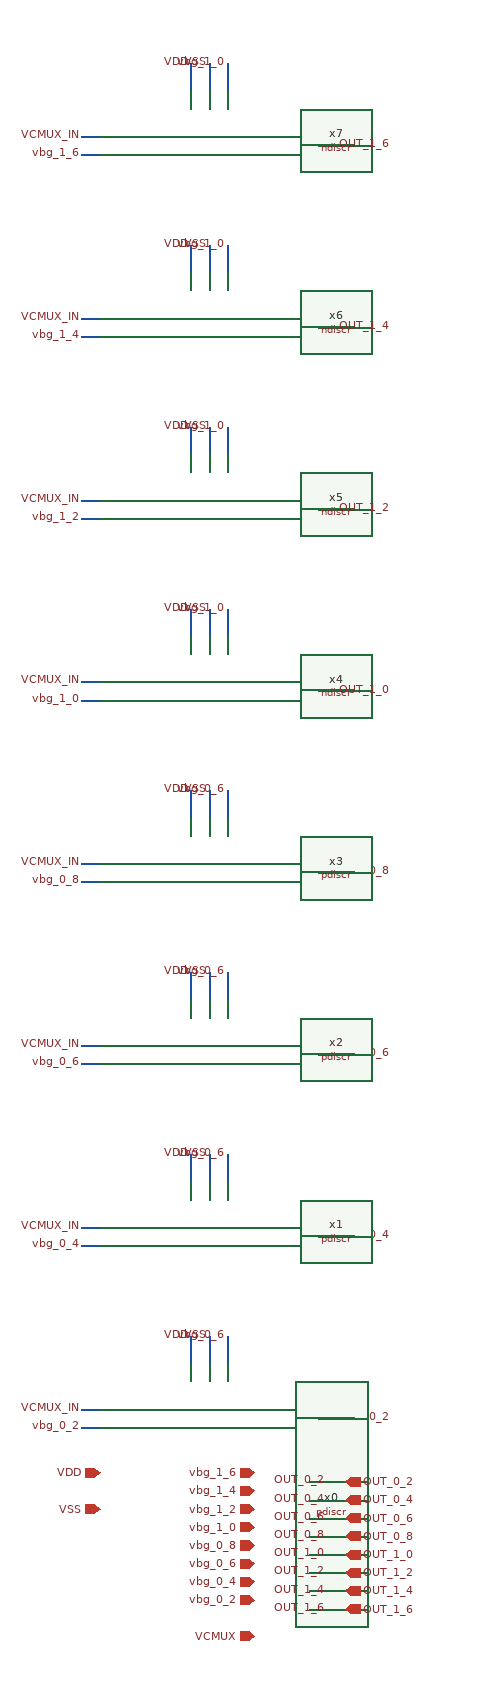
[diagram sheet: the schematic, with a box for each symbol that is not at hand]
v {xschem version=3.4.5 file_version=1.2
}
G {}
K {}
V {}
S {}
E {}
N 160 -130 160 -100 {
lab=vbg_0_6}
N 120 -130 120 -100 {
lab=VDD}
N 140 -130 140 -100 {
lab=VSS}
N 0 -50 20 -50 {
lab=VCMUX_IN}
N 0 -30 20 -30 {
lab=vbg_0_2}
N 260 -40 300 -40 {
lab=OUT_0_2}
N 160 -330 160 -300 {
lab=vbg_0_6}
N 120 -330 120 -300 {
lab=VDD}
N 140 -330 140 -300 {
lab=VSS}
N 0 -250 20 -250 {
lab=VCMUX_IN}
N 0 -230 20 -230 {
lab=vbg_0_4}
N 260 -240 300 -240 {
lab=OUT_0_4}
N 160 -530 160 -500 {
lab=vbg_0_6}
N 120 -530 120 -500 {
lab=VDD}
N 140 -530 140 -500 {
lab=VSS}
N 0 -450 20 -450 {
lab=VCMUX_IN}
N 0 -430 20 -430 {
lab=vbg_0_6}
N 260 -440 300 -440 {
lab=OUT_0_6}
N 160 -730 160 -700 {
lab=vbg_0_6}
N 120 -730 120 -700 {
lab=VDD}
N 140 -730 140 -700 {
lab=VSS}
N 0 -650 20 -650 {
lab=VCMUX_IN}
N 0 -630 20 -630 {
lab=vbg_0_8}
N 260 -640 300 -640 {
lab=OUT_0_8}
N 0 -850 20 -850 {
lab=VCMUX_IN}
N 0 -830 20 -830 {
lab=vbg_1_0}
N 160 -930 160 -900 {
lab=vbg_1_0}
N 120 -930 120 -900 {
lab=VDD}
N 140 -930 140 -900 {
lab=VSS}
N 260 -840 300 -840 {
lab=OUT_1_0}
N 0 -1050 20 -1050 {
lab=VCMUX_IN}
N 0 -1030 20 -1030 {
lab=vbg_1_2}
N 160 -1130 160 -1100 {
lab=vbg_1_0}
N 120 -1130 120 -1100 {
lab=VDD}
N 140 -1130 140 -1100 {
lab=VSS}
N 260 -1040 300 -1040 {
lab=OUT_1_2}
N 0 -1250 20 -1250 {
lab=VCMUX_IN}
N 0 -1230 20 -1230 {
lab=vbg_1_4}
N 160 -1330 160 -1300 {
lab=vbg_1_0}
N 120 -1330 120 -1300 {
lab=VDD}
N 140 -1330 140 -1300 {
lab=VSS}
N 260 -1240 300 -1240 {
lab=OUT_1_4}
N 0 -1450 20 -1450 {
lab=VCMUX_IN}
N 0 -1430 20 -1430 {
lab=vbg_1_6}
N 160 -1530 160 -1500 {
lab=vbg_1_0}
N 120 -1530 120 -1500 {
lab=VDD}
N 140 -1530 140 -1500 {
lab=VSS}
N 260 -1440 300 -1440 {
lab=OUT_1_6}
N 250 30 290 30 {
lab=OUT_0_2}
N 250 50 290 50 {
lab=OUT_0_4}
N 250 90 290 90 {
lab=OUT_0_8}
N 250 110 290 110 {
lab=OUT_1_0}
N 250 130 290 130 {
lab=OUT_1_2}
N 250 150 290 150 {
lab=OUT_1_4}
N 250 170 290 170 {
lab=OUT_1_6}
N 250 70 290 70 {
lab=OUT_0_6}
C {devices/lab_wire.sym} 120 -130 3 1 {name=p20 sig_type=std_logic lab=VDD}
C {devices/lab_wire.sym} 140 -130 3 1 {name=p26 sig_type=std_logic lab=VSS}
C {devices/lab_wire.sym} 160 -130 3 1 {name=p27 sig_type=std_logic lab=vbg_0_6}
C {devices/lab_wire.sym} 0 -50 0 0 {name=p28 sig_type=std_logic lab=VCMUX_IN}
C {devices/lab_wire.sym} 0 -30 0 0 {name=p29 sig_type=std_logic lab=vbg_0_2}
C {devices/lab_wire.sym} 280 -40 0 1 {name=p33 sig_type=std_logic lab=OUT_0_2}
C {pdiscr.sym} 20 -40 0 0 {name=x0}
C {devices/lab_wire.sym} 120 -330 3 1 {name=p1 sig_type=std_logic lab=VDD}
C {devices/lab_wire.sym} 140 -330 3 1 {name=p2 sig_type=std_logic lab=VSS}
C {devices/lab_wire.sym} 160 -330 3 1 {name=p3 sig_type=std_logic lab=vbg_0_6}
C {devices/lab_wire.sym} 0 -250 0 0 {name=p4 sig_type=std_logic lab=VCMUX_IN}
C {devices/lab_wire.sym} 0 -230 0 0 {name=p5 sig_type=std_logic lab=vbg_0_4}
C {devices/lab_wire.sym} 280 -240 0 1 {name=p6 sig_type=std_logic lab=OUT_0_4}
C {pdiscr.sym} 20 -240 0 0 {name=x1}
C {devices/lab_wire.sym} 120 -530 3 1 {name=p7 sig_type=std_logic lab=VDD}
C {devices/lab_wire.sym} 140 -530 3 1 {name=p8 sig_type=std_logic lab=VSS}
C {devices/lab_wire.sym} 160 -530 3 1 {name=p9 sig_type=std_logic lab=vbg_0_6}
C {devices/lab_wire.sym} 0 -450 0 0 {name=p10 sig_type=std_logic lab=VCMUX_IN}
C {devices/lab_wire.sym} 0 -430 0 0 {name=p11 sig_type=std_logic lab=vbg_0_6}
C {devices/lab_wire.sym} 280 -440 0 1 {name=p12 sig_type=std_logic lab=OUT_0_6}
C {pdiscr.sym} 20 -440 0 0 {name=x2}
C {devices/lab_wire.sym} 120 -730 3 1 {name=p13 sig_type=std_logic lab=VDD}
C {devices/lab_wire.sym} 140 -730 3 1 {name=p14 sig_type=std_logic lab=VSS}
C {devices/lab_wire.sym} 160 -730 3 1 {name=p15 sig_type=std_logic lab=vbg_0_6}
C {devices/lab_wire.sym} 0 -650 0 0 {name=p16 sig_type=std_logic lab=VCMUX_IN}
C {devices/lab_wire.sym} 0 -630 0 0 {name=p17 sig_type=std_logic lab=vbg_0_8}
C {devices/lab_wire.sym} 280 -640 0 1 {name=p18 sig_type=std_logic lab=OUT_0_8}
C {pdiscr.sym} 20 -640 0 0 {name=x3}
C {ndiscr.sym} 20 -840 0 0 {name=x4}
C {devices/lab_wire.sym} 0 -850 0 0 {name=p19 sig_type=std_logic lab=VCMUX_IN}
C {devices/lab_wire.sym} 0 -830 0 0 {name=p21 sig_type=std_logic lab=vbg_1_0}
C {devices/lab_wire.sym} 120 -930 3 1 {name=p22 sig_type=std_logic lab=VDD}
C {devices/lab_wire.sym} 140 -930 3 1 {name=p23 sig_type=std_logic lab=VSS}
C {devices/lab_wire.sym} 160 -930 3 1 {name=p24 sig_type=std_logic lab=vbg_1_0}
C {devices/lab_wire.sym} 280 -840 0 1 {name=p25 sig_type=std_logic lab=OUT_1_0}
C {ndiscr.sym} 20 -1040 0 0 {name=x5}
C {devices/lab_wire.sym} 0 -1050 0 0 {name=p30 sig_type=std_logic lab=VCMUX_IN}
C {devices/lab_wire.sym} 0 -1030 0 0 {name=p31 sig_type=std_logic lab=vbg_1_2}
C {devices/lab_wire.sym} 120 -1130 3 1 {name=p32 sig_type=std_logic lab=VDD}
C {devices/lab_wire.sym} 140 -1130 3 1 {name=p34 sig_type=std_logic lab=VSS}
C {devices/lab_wire.sym} 160 -1130 3 1 {name=p35 sig_type=std_logic lab=vbg_1_0}
C {devices/lab_wire.sym} 280 -1040 0 1 {name=p36 sig_type=std_logic lab=OUT_1_2}
C {ndiscr.sym} 20 -1240 0 0 {name=x6}
C {devices/lab_wire.sym} 0 -1250 0 0 {name=p37 sig_type=std_logic lab=VCMUX_IN}
C {devices/lab_wire.sym} 0 -1230 0 0 {name=p38 sig_type=std_logic lab=vbg_1_4}
C {devices/lab_wire.sym} 120 -1330 3 1 {name=p39 sig_type=std_logic lab=VDD}
C {devices/lab_wire.sym} 140 -1330 3 1 {name=p40 sig_type=std_logic lab=VSS}
C {devices/lab_wire.sym} 160 -1330 3 1 {name=p41 sig_type=std_logic lab=vbg_1_0}
C {devices/lab_wire.sym} 280 -1240 0 1 {name=p42 sig_type=std_logic lab=OUT_1_4}
C {ndiscr.sym} 20 -1440 0 0 {name=x7}
C {devices/lab_wire.sym} 0 -1450 0 0 {name=p43 sig_type=std_logic lab=VCMUX_IN}
C {devices/lab_wire.sym} 0 -1430 0 0 {name=p44 sig_type=std_logic lab=vbg_1_6}
C {devices/lab_wire.sym} 120 -1530 3 1 {name=p45 sig_type=std_logic lab=VDD}
C {devices/lab_wire.sym} 140 -1530 3 1 {name=p46 sig_type=std_logic lab=VSS}
C {devices/lab_wire.sym} 160 -1530 3 1 {name=p47 sig_type=std_logic lab=vbg_1_0}
C {devices/lab_wire.sym} 280 -1440 0 1 {name=p48 sig_type=std_logic lab=OUT_1_6}
C {devices/iopin.sym} 20 20 0 0 {name=p49 lab=VDD}
C {devices/iopin.sym} 20 60 0 0 {name=p50 lab=VSS}
C {devices/opin.sym} 290 30 0 0 {name=p51 sig_type=std_logic lab=OUT_0_2}
C {devices/lab_wire.sym} 270 30 0 0 {name=p52 sig_type=std_logic lab=OUT_0_2}
C {devices/opin.sym} 290 50 0 0 {name=p53 sig_type=std_logic lab=OUT_0_4}
C {devices/lab_wire.sym} 270 50 0 0 {name=p54 sig_type=std_logic lab=OUT_0_4}
C {devices/opin.sym} 290 90 0 0 {name=p55 sig_type=std_logic lab=OUT_0_8}
C {devices/lab_wire.sym} 270 90 0 0 {name=p56 sig_type=std_logic lab=OUT_0_8}
C {devices/opin.sym} 290 110 0 0 {name=p57 sig_type=std_logic lab=OUT_1_0}
C {devices/lab_wire.sym} 270 110 0 0 {name=p58 sig_type=std_logic lab=OUT_1_0}
C {devices/opin.sym} 290 130 0 0 {name=p59 sig_type=std_logic lab=OUT_1_2}
C {devices/lab_wire.sym} 270 130 0 0 {name=p60 sig_type=std_logic lab=OUT_1_2}
C {devices/opin.sym} 290 150 0 0 {name=p61 sig_type=std_logic lab=OUT_1_4}
C {devices/lab_wire.sym} 270 150 0 0 {name=p62 sig_type=std_logic lab=OUT_1_4}
C {devices/opin.sym} 290 170 0 0 {name=p63 sig_type=std_logic lab=OUT_1_6}
C {devices/lab_wire.sym} 270 170 0 0 {name=p64 sig_type=std_logic lab=OUT_1_6}
C {devices/opin.sym} 290 70 0 0 {name=p65 sig_type=std_logic lab=OUT_0_6}
C {devices/lab_wire.sym} 270 70 0 0 {name=p66 sig_type=std_logic lab=OUT_0_6}
C {devices/ipin.sym} 190 20 0 0 {name=p67 lab=vbg_1_6}
C {devices/ipin.sym} 190 40 0 0 {name=p68 lab=vbg_1_4}
C {devices/ipin.sym} 190 60 0 0 {name=p69 lab=vbg_1_2}
C {devices/ipin.sym} 190 80 0 0 {name=p70 lab=vbg_1_0}
C {devices/ipin.sym} 190 100 0 0 {name=p71 lab=vbg_0_8}
C {devices/ipin.sym} 190 120 0 0 {name=p72 lab=vbg_0_6}
C {devices/ipin.sym} 190 140 0 0 {name=p73 lab=vbg_0_4}
C {devices/ipin.sym} 190 160 0 0 {name=p74 lab=vbg_0_2}
C {devices/ipin.sym} 190 200 0 0 {name=p75 lab=VCMUX}
